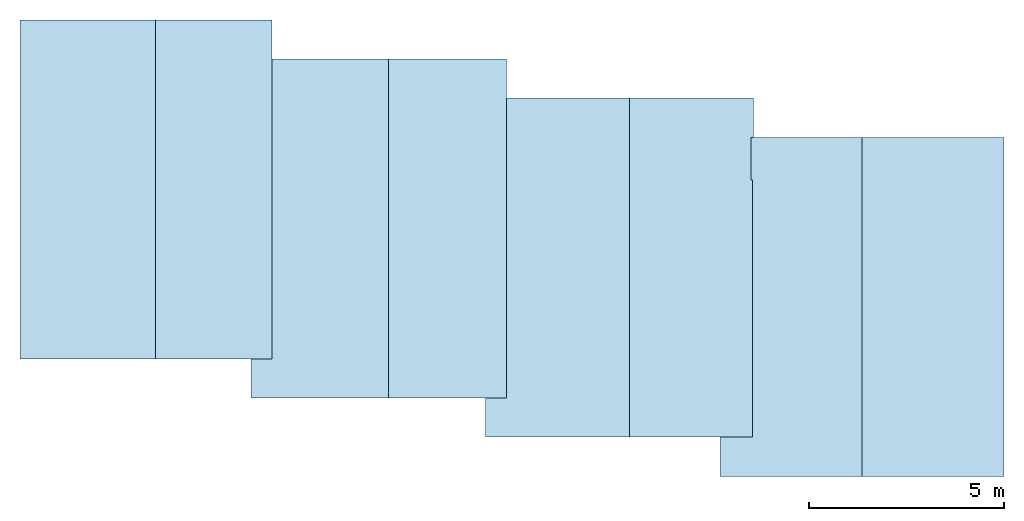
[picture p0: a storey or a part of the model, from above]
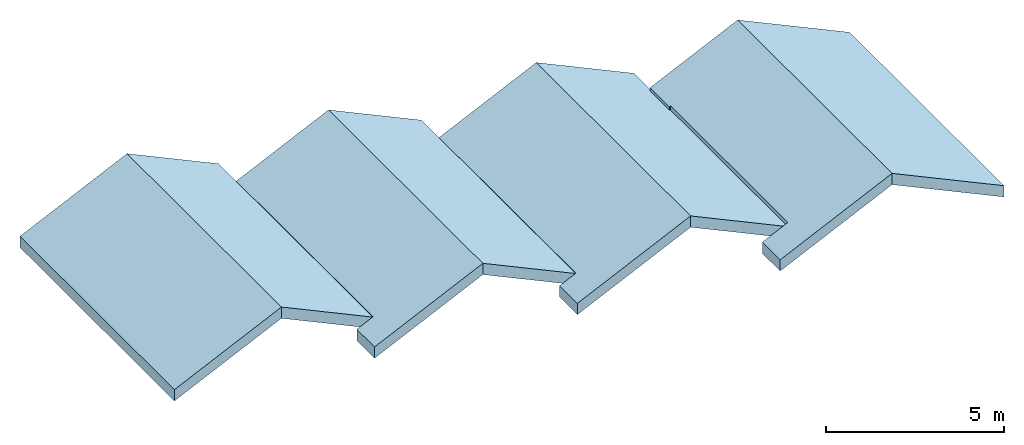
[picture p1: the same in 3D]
Properties of the parts of a building model (IFC2X3)

# File
Description: ViewDefinition [CoordinationView_V2.0], RevitIdentifiers [ContentGUID: f3c95b2a-3cce-4d3e-a499-3f45440ba017, VersionGUID: e7a1cec6-75d4-45cd-a237-02611641ebe7, NumberOfSaves: 51], CoordinateReference [CoordinateBase: Shared Coordinates]
File name: Skogtun nytt bygg.ifc
Time: 2026-06-24T11:29:21+01:00
Written by: ODA SDAI 25.12
Made in: Autodesk - Revit 26.3.0.37 (ENU) - 26.3.0.37

# IfcProject, 2009
LongName: Skogtun nye boliger; Phase: Prosjektstatus

# IfcSite, Default
RefLatitude: 59, 55, 1, 432800; RefLongitude: 10, 43, 39, 810104; RefElevation: 0 mm

# IfcBuilding
Pset_BuildingCommon - NumberOfStoreys: 4

# IfcBuildingStorey (4)
Pset_AirSideSystemInformation - sets with these values: 2
Name | LongName = Name | Elevation (mm)
Et. 1 | Et. 1 | 0
Et. 2 | Et. 2 | 2681
Gesims | Gesims | 5081
Møne | Møne | 6650

# IfcSpace: Area 1:1055046, 1
In: Et. 1
LongName: Area; InteriorOrExteriorSpace: INTERNAL; Group: Gross Building
Pset_AirSideSystemInformation - Name: Area; sets with these values: 2
Pset_SpaceCommon - Reference: Area 1

# IfcSpace: Bad 203:1075184, 203
In: Et. 2
LongName: Bad; InteriorOrExteriorSpace: INTERNAL
Pset_AirSideSystemInformation - Name: Bad; sets with these values: 2
Pset_SpaceCommon - Reference: Bad 203

# IfcSpace: Bad 207:1079033, 207
In: Et. 2
LongName: Bad; InteriorOrExteriorSpace: INTERNAL
Pset_AirSideSystemInformation - Name: Bad; sets with these values: 2
Pset_SpaceCommon - Reference: Bad 207

# IfcSpace: Bad 211:1079045, 211
In: Et. 2
LongName: Bad; InteriorOrExteriorSpace: INTERNAL
Pset_AirSideSystemInformation - Name: Bad; sets with these values: 2
Pset_SpaceCommon - Reference: Bad 211

# IfcSpace: Bad 215:1079057, 215
In: Et. 2
LongName: Bad; InteriorOrExteriorSpace: INTERNAL
Pset_AirSideSystemInformation - Name: Bad; sets with these values: 2
Pset_SpaceCommon - Reference: Bad 215

# IfcSpace: Bod 104:1043827, 104
In: Et. 1
LongName: Bod; InteriorOrExteriorSpace: INTERNAL
Pset_AirSideSystemInformation - Name: Bod; sets with these values: 2
Pset_SpaceCommon - Reference: Bod 104

# IfcSpace: Bod 108:1043835, 108
In: Et. 1
LongName: Bod; InteriorOrExteriorSpace: INTERNAL
Pset_AirSideSystemInformation - Name: Bod; sets with these values: 2
Pset_SpaceCommon - Reference: Bod 108

# IfcSpace: Bod 112:1043838, 112
In: Et. 1
LongName: Bod; InteriorOrExteriorSpace: INTERNAL
Pset_AirSideSystemInformation - Name: Bod; sets with these values: 2
Pset_SpaceCommon - Reference: Bod 112

# IfcSpace: Bod 116:1043841, 116
In: Et. 1
LongName: Bod; InteriorOrExteriorSpace: INTERNAL
Pset_AirSideSystemInformation - Name: Bod; sets with these values: 2
Pset_SpaceCommon - Reference: Bod 116

# IfcSpace: Gang 103:1063782, 103
In: Et. 1
LongName: Gang; InteriorOrExteriorSpace: INTERNAL
Pset_AirSideSystemInformation - Name: Gang; sets with these values: 2
Pset_SpaceCommon - Reference: Gang 103

# IfcSpace: Gang 107:1080082, 107
In: Et. 1
LongName: Gang; InteriorOrExteriorSpace: INTERNAL
Pset_AirSideSystemInformation - Name: Gang; sets with these values: 2
Pset_SpaceCommon - Reference: Gang 107

# IfcSpace: Gang 111:1080092, 111
In: Et. 1
LongName: Gang; InteriorOrExteriorSpace: INTERNAL
Pset_AirSideSystemInformation - Name: Gang; sets with these values: 2
Pset_SpaceCommon - Reference: Gang 111

# IfcSpace: Gang 115:1080101, 115
In: Et. 1
LongName: Gang; InteriorOrExteriorSpace: INTERNAL
Pset_AirSideSystemInformation - Name: Gang; sets with these values: 2
Pset_SpaceCommon - Reference: Gang 115

# IfcSpace: Gang 204:1075187, 204
In: Et. 2
LongName: Gang; InteriorOrExteriorSpace: INTERNAL
Pset_AirSideSystemInformation - Name: Gang; sets with these values: 2
Pset_SpaceCommon - Reference: Gang 204

# IfcSpace: Gang 208:1079036, 208
In: Et. 2
LongName: Gang; InteriorOrExteriorSpace: INTERNAL
Pset_AirSideSystemInformation - Name: Gang; sets with these values: 2
Pset_SpaceCommon - Reference: Gang 208

# IfcSpace: Gang 212:1079048, 212
In: Et. 2
LongName: Gang; InteriorOrExteriorSpace: INTERNAL
Pset_AirSideSystemInformation - Name: Gang; sets with these values: 2
Pset_SpaceCommon - Reference: Gang 212

# IfcSpace: Gang 216:1079060, 216
In: Et. 2
LongName: Gang; InteriorOrExteriorSpace: INTERNAL
Pset_AirSideSystemInformation - Name: Gang; sets with these values: 2
Pset_SpaceCommon - Reference: Gang 216

# IfcSpace: Soverom 201:1075173, 201
In: Et. 2
LongName: Soverom; InteriorOrExteriorSpace: INTERNAL
Pset_AirSideSystemInformation - Name: Soverom; sets with these values: 2
Pset_SpaceCommon - Reference: Soverom 201

# IfcSpace: Soverom 202:1075181, 202
In: Et. 2
LongName: Soverom; InteriorOrExteriorSpace: INTERNAL
Pset_AirSideSystemInformation - Name: Soverom; sets with these values: 2
Pset_SpaceCommon - Reference: Soverom 202

# IfcSpace: Soverom 205:1079027, 205
In: Et. 2
LongName: Soverom; InteriorOrExteriorSpace: INTERNAL
Pset_AirSideSystemInformation - Name: Soverom; sets with these values: 2
Pset_SpaceCommon - Reference: Soverom 205

# IfcSpace: Soverom 206:1079030, 206
In: Et. 2
LongName: Soverom; InteriorOrExteriorSpace: INTERNAL
Pset_AirSideSystemInformation - Name: Soverom; sets with these values: 2
Pset_SpaceCommon - Reference: Soverom 206

# IfcSpace: Soverom 209:1079039, 209
In: Et. 2
LongName: Soverom; InteriorOrExteriorSpace: INTERNAL
Pset_AirSideSystemInformation - Name: Soverom; sets with these values: 2
Pset_SpaceCommon - Reference: Soverom 209

# IfcSpace: Soverom 210:1079042, 210
In: Et. 2
LongName: Soverom; InteriorOrExteriorSpace: INTERNAL
Pset_AirSideSystemInformation - Name: Soverom; sets with these values: 2
Pset_SpaceCommon - Reference: Soverom 210

# IfcSpace: Soverom 213:1079051, 213
In: Et. 2
LongName: Soverom; InteriorOrExteriorSpace: INTERNAL
Pset_AirSideSystemInformation - Name: Soverom; sets with these values: 2
Pset_SpaceCommon - Reference: Soverom 213

# IfcSpace: Soverom 214:1079054, 214
In: Et. 2
LongName: Soverom; InteriorOrExteriorSpace: INTERNAL
Pset_AirSideSystemInformation - Name: Soverom; sets with these values: 2
Pset_SpaceCommon - Reference: Soverom 214

# IfcSpace: Stue/Kjøkken 101:1063785, 101
In: Et. 1
LongName: Stue/Kjøkken; InteriorOrExteriorSpace: INTERNAL
Pset_AirSideSystemInformation - Name: Stue/Kjøkken; sets with these values: 2
Pset_SpaceCommon - Reference: Stue/Kjøkken 101

# IfcSpace: Stue/Kjøkken 105:1080072, 105
In: Et. 1
LongName: Stue/Kjøkken; InteriorOrExteriorSpace: INTERNAL
Pset_AirSideSystemInformation - Name: Stue/Kjøkken; sets with these values: 2
Pset_SpaceCommon - Reference: Stue/Kjøkken 105

# IfcSpace: Stue/Kjøkken 109:1080085, 109
In: Et. 1
LongName: Stue/Kjøkken; InteriorOrExteriorSpace: INTERNAL
Pset_AirSideSystemInformation - Name: Stue/Kjøkken; sets with these values: 2
Pset_SpaceCommon - Reference: Stue/Kjøkken 109

# IfcSpace: Stue/Kjøkken 113:1080095, 113
In: Et. 1
LongName: Stue/Kjøkken; InteriorOrExteriorSpace: INTERNAL
Pset_AirSideSystemInformation - Name: Stue/Kjøkken; sets with these values: 2
Pset_SpaceCommon - Reference: Stue/Kjøkken 113

# IfcSpace: WC 102:1063779, 102
In: Et. 1
LongName: WC; InteriorOrExteriorSpace: INTERNAL
Pset_AirSideSystemInformation - Name: WC; sets with these values: 2
Pset_SpaceCommon - Reference: WC 102

# IfcSpace: WC 106:1080079, 106
In: Et. 1
LongName: WC; InteriorOrExteriorSpace: INTERNAL
Pset_AirSideSystemInformation - Name: WC; sets with these values: 2
Pset_SpaceCommon - Reference: WC 106

# IfcSpace: WC 110:1080089, 110
In: Et. 1
LongName: WC; InteriorOrExteriorSpace: INTERNAL
Pset_AirSideSystemInformation - Name: WC; sets with these values: 2
Pset_SpaceCommon - Reference: WC 110

# IfcSpace: WC 114:1080098, 114
In: Et. 1
LongName: WC; InteriorOrExteriorSpace: INTERNAL
Pset_AirSideSystemInformation - Name: WC; sets with these values: 2
Pset_SpaceCommon - Reference: WC 114

# IfcBuildingElementProxy: HC-Sirkel:HC-Sirkel 1500 (4)
Type - Material: <Unnamed>
Pset_BuildingElementProxyCommon - Reference: HC-Sirkel 1500; sets with these values: 2
Name (HC-Sirkel:HC-Sirkel 1500:...) | In
1074592 | 203
1075893 | 207
1076030 | 211
1076237 | 215

# IfcBuildingElementProxy: Kombiskap:Kombiskap (4)
Type - Material: Kjøkken - Hvitevarer
Pset_BuildingElementProxyCommon - Reference: Kombiskap; sets with these values: 2
Name (Kombiskap:Kombiskap:...) | In
1079378 | 113
1089154 | 109
1089204 | 105
1089252 | 101

# IfcBuildingElementProxy: Komfyr:Komfyr (4)
Type - Material: <Unnamed>, Focus - Material - Platetopp, Kjøkken - Hvitevarer, Kjøkken - Hvitevarer Glass, Material Stekeovn
Pset_BuildingElementProxyCommon - Reference: Komfyr; sets with these values: 2
Name (Komfyr:Komfyr:...) | In
1079377 | 113
1089153 | 109
1089203 | 105
1089251 | 101

# IfcBuildingElementProxy: Vaskesøyle:Vaskesøyle (4)
Type - Material: Bad-Vask-Maskin-Hvit, Stål-Børstet, Plastikk - Sort, Bad-Vask-Maskin-Glass
Pset_BuildingElementProxyCommon - Reference: Vaskesøyle; sets with these values: 2
Name (Vaskesøyle:Vaskesøyle:...) | In
1072654 | 203
1075889 | 207
1076026 | 211
1076233 | 215

# IfcColumn: Limtre-søyle:Limtre 90x90 (2)
Type - PredefinedType: COLUMN; Material: Limtre - GL30c
Type - Pset_ColumnCommon - LoadBearing: yes
Pset_ColumnCommon - IsExternal: no; Reference: Limtre 90x90
Pset_QuantityTakeOff - Reference: Limtre 90x90; sets with these values: 2
Name (Limtre-søyle:Limtre 90x90:...) | In
896741 | Et. 1 | Pset_ColumnCommon - Slope: 0 deg
1055478 | Et. 2

# IfcCovering: Fascia:Vindski, Fascia:Vindski:1044949
In: Et. 1
Type - Pset_CoveringCommon - Material: Maling - Hvit
Material: Maling - Hvit
Pset_CoveringCommon - Reference: Vindski; sets with these values: 2

# IfcDoor: ID Hel:9x21M (8)
Type - OperationType: SINGLE_SWING_LEFT; ParameterTakesPrecedence: no; Sizeable: no; Material: Dør - Håndtak, Karm, Dør - Dørblad
Type - ID Hel:9x21M:1059161:1 - PanelOperation: SWINGING
OverallHeight: 2100 mm; OverallWidth: 910 mm
Pset_DoorCommon - IsExternal: no; Reference: 9x21M
Pset_QuantityTakeOff - Reference: 9x21M
Name (ID Hel:9x21M:...) | In
1059161 | Et. 1
1073074 | Et. 2
1075891 | Et. 2
1076028 | Et. 2
1076235 | Et. 2
1079270 | Et. 1
1079330 | Et. 1
1079388 | Et. 1

# IfcDoor: ID Hel:9x21M (8)
In: Et. 2
Type - OperationType: SINGLE_SWING_RIGHT; ParameterTakesPrecedence: no; Sizeable: no; Material: Dør - Håndtak, Karm, Dør - Dørblad
Type - ID Hel:9x21M:1073016:1 - PanelOperation: SWINGING
OverallHeight: 2100 mm; OverallWidth: 910 mm
Pset_DoorCommon - IsExternal: no; Reference: 9x21M
Pset_QuantityTakeOff - Reference: 9x21M
Name (ID Hel:9x21M:...)
1073016
1073219
1075890
1075892
1076027
1076029
1076234
1076236

# IfcDoor: YD 1 Glassfelt omramming:10x21M (4)
In: Et. 1
Type - OperationType: SINGLE_SWING_RIGHT; ParameterTakesPrecedence: no; Sizeable: no; Material: Karm, Dør - Håndtak, Glass - Klart, Dør - Dørblad, Dør - Terskel - Eik
Type - YD 1 Glassfelt omramming:10x21M:887120:1 - PanelOperation: SWINGING
OverallHeight: 2100 mm; OverallWidth: 1010 mm
Pset_DoorCommon - IsExternal: yes; Reference: 10x21M
Pset_QuantityTakeOff - Reference: 10x21M
Name (YD 1 Glassfelt omramming:10x21M:...)
887120
887285
887393
887469

# IfcDoor: YD Dynamiske sprosser omramming:9x21M (4)
In: Et. 2
Type - ParameterTakesPrecedence: no; Sizeable: no; Material: Dør - Dørblad, Karm, Dør - Håndtak, Glass - Klart, Dør - Terskel - Eik
OverallHeight: 2100 mm; OverallWidth: 910 mm
Pset_DoorCommon - IsExternal: yes; Reference: 9x21M
Pset_QuantityTakeOff - Reference: 9x21M
Name (YD Dynamiske sprosser omramming:9x21M:...)
918485
918542
1065238
1078465

# IfcDoor: YD Hel omramming:10x21M (4)
In: Et. 1
Type - OperationType: SINGLE_SWING_LEFT; ParameterTakesPrecedence: no; Sizeable: no; Material: Karm, Dør - Håndtak, Dør - Dørblad, Dør - Terskel - Eik
Type - YD Hel omramming:10x21M:893311:1 - PanelOperation: SWINGING
OverallHeight: 2100 mm; OverallWidth: 1010 mm
Pset_DoorCommon - IsExternal: yes; Reference: 10x21M
Pset_QuantityTakeOff - Reference: 10x21M
Name (YD Hel omramming:10x21M:...)
893311
893358
893382
893453

# IfcFlowTerminal: Dusjkabinett:315_Dusjkabinett_900x900mm (4)
Type - Material: Bad-Innredning-Krom, Bad-Innredning-Glass-Klar, Bad-Innredning-Porselen, Bad-Innredning-dusjkabinett-Hvit
Pset_DistributionFlowElementCommon - Reference: 315_Dusjkabinett_900x900mm; sets with these values: 2
Name (Dusjkabinett:315_Dusjkabinett_900x900mm:...) | In
988469 | 203
1075785 | 207
1075992 | 211
1076199 | 215

# IfcFlowTerminal: Focus-Toalett gulv 1:Focus-Toalett gulv 1 (8)
Type - Material: Focus - VVS - Toalett, Focus - VVS - Toalett lokk, Focus - VVS - Krom
Pset_DistributionFlowElementCommon - Reference: Focus-Toalett gulv 1; sets with these values: 2
Name (Focus-Toalett gulv 1:Focus-Toalett gulv 1:...) | In
929392 | 102
989158 | 203
1075787 | 207
1075994 | 211
1076201 | 215
1079249 | 106
1079309 | 110
1079367 | 114

# IfcFlowTerminal: Klassisk - Kjøkkenvask 1,5 kum:600mm høyre (4)
Type - Material: Steel, Chrome Plated, Focus - Kjøkken - Kran, <Unnamed>, Focus - Kjøkken - Vask
Pset_DistributionFlowElementCommon - Reference: 600mm høyre; sets with these values: 2
Name (Klassisk - Kjøkkenvask 1,5 kum:600mm høyre:...) | In
1079379 | 113
1089155 | 109
1089205 | 105
1089253 | 101

# IfcFurnishingElement: Bad_Innredning_Indigo_600:274-IK-Vågen-600 (8)
Type - Material: Bad-Innredning-Krom, Bad-Innredning-Porselen, Bad-Innredning-Skrog, Bad-Innredning-Front-Hvit, Bad-Innredning-Speil, Bad-Innredning-Håndtak-Stål
Pset_QuantityTakeOff - Reference: 274-IK-Vågen-600
Name (Bad_Innredning_Indigo_600:274-IK-Vågen-600:...) | In
922596 | 102
989017 | 203
1075786 | 207
1075993 | 211
1076200 | 215
1079248 | 106
1079308 | 110
1079366 | 114

# IfcFurnishingElement: Focus - Håndtak Skap:Håndtak skap (28)
Type - Material: Focus - Kjøkken - Håndtak
Pset_QuantityTakeOff - Reference: Håndtak skap
Name (Focus - Håndtak Skap:Håndtak skap:...) | In
1079375 | 113
1079376 | 113
1086313 | 113
1088307 | 113
1088308 | 113
1089151 | 109
1089152 | 109
1089161 | 109
1089163 | 109
1089164 | 109
1089201 | 105
1089202 | 105
1089211 | 105
1089213 | 105
1089214 | 105
1089249 | 101
1089250 | 101
1089259 | 101
1089261 | 101
1089262 | 101
1096429 | 113
1096430 | 113
1096527 | 113
1096528 | 113
1097146 | 113
1097147 | 113
1097175 | 113
1097176 | 113

# IfcFurnishingElement: Focus - Håndtak Skuff:Håndtak skuff (24)
Type - Material: Focus - Kjøkken - Håndtak
Pset_QuantityTakeOff - Reference: Håndtak skuff
Name (Focus - Håndtak Skuff:Håndtak skuff:...) | In
1079371 | 113
1079372 | 113
1079373 | 113
1079391 | 113
1079392 | 113
1079393 | 113
1089147 | 109
1089148 | 109
1089149 | 109
1089157 | 109
1089158 | 109
1089159 | 109
1089197 | 105
1089198 | 105
1089199 | 105
1089207 | 105
1089208 | 105
1089209 | 105
1089245 | 101
1089246 | 101
1089247 | 101
1089255 | 101
1089256 | 101
1089257 | 101

# IfcFurnishingElement: Focus - Kjøkken - Benkeplate Hjørne:Focus - Kjøkken - Benkeplate Hjørne (4)
Type - Material: Focus - Material - Benkeplate
Pset_QuantityTakeOff - Reference: Focus - Kjøkken - Benkeplate Hjørne
Name (Focus - Kjøkken - Benkeplate Hjørne:Focus - Kjøkken - Benkeplate Hjørne:...) | In
1088530 | 113
1089165 | 109
1089215 | 105
1089263 | 101

# IfcFurnishingElement: Focus - Kjøkken - Benkeskap 2 dører:800 mm (4)
Type - Material: Focus - Kjøkken - Front, Focus - Kjøkken - Skapstamme
Pset_QuantityTakeOff - Reference: 800 mm
Name (Focus - Kjøkken - Benkeskap 2 dører:800 mm:...) | In
1079374 | 113
1089150 | 109
1089200 | 105
1089248 | 101

# IfcFurnishingElement: Focus - Kjøkken - Benkeskap 3 skuffer:600 mm (8)
Type - Material: Focus - Kjøkken - Front, Focus - Kjøkken - Skapstamme
Pset_QuantityTakeOff - Reference: 600 mm
Name (Focus - Kjøkken - Benkeskap 3 skuffer:600 mm:...) | In
1079370 | 113
1079390 | 113
1089146 | 109
1089156 | 109
1089196 | 105
1089206 | 105
1089244 | 101
1089254 | 101

# IfcFurnishingElement: Focus - Kjøkken - Benkeskap Hjørne:1000x650 mm (4)
Type - Material: Focus - Kjøkken - Front, Focus - Kjøkken - Skapstamme
Pset_QuantityTakeOff - Reference: 1000x650 mm
Name (Focus - Kjøkken - Benkeskap Hjørne:1000x650 mm:...) | In
1086312 | 113
1089160 | 109
1089210 | 105
1089258 | 101

# IfcFurnishingElement: Focus - Kjøkken - Høyskap 2 dører:600 mm (4)
Type - Material: Focus - Kjøkken - Front, Focus - Kjøkken - Skapstamme
Pset_QuantityTakeOff - Reference: 600 mm
Name (Focus - Kjøkken - Høyskap 2 dører:600 mm:...) | In
1088306 | 113
1089162 | 109
1089212 | 105
1089260 | 101

# IfcFurnishingElement: Focus - Kjøkken - Spiseplass:4 pers (4)
Type - Material: Focus - Møbler - Spisebord, Focus - Stolsete
Pset_QuantityTakeOff - Reference: 4 pers
Name (Focus - Kjøkken - Spiseplass:4 pers:...) | In
961817 | 101
1079251 | 105
1079311 | 109
1079369 | 113

# IfcFurnishingElement: Focus - Kjøkken - Veggskap 2 dør:600x370x400 (4)
In: 113
Type - Material: Focus - Kjøkken - Front, Focus - Kjøkken - Skapstamme
Pset_QuantityTakeOff - Reference: 600x370x400
Name (Focus - Kjøkken - Veggskap 2 dør:600x370x400:...)
1096428
1096526
1097145
1097174

# IfcFurnishingElement: Focus Garderobeskap - Skyvedører 2 slette:100x60x220 (8)
Type - Material: Møbler - Hvit
Pset_QuantityTakeOff - Reference: 100x60x220
Name (Focus Garderobeskap - Skyvedører 2 slette:100x60x220:...) | In
931345 | 103
985279 | 201
1075784 | 205
1075991 | 209
1076198 | 213
1079250 | 107
1079310 | 111
1079368 | 115

# IfcFurnishingElement: Focus Garderobeskap - Skyvedører 3 slette:150x60x220 (4)
Type - Material: Møbler - Hvit, Møbler - Grå mørk
Pset_QuantityTakeOff - Reference: 150x60x220
Name (Focus Garderobeskap - Skyvedører 3 slette:150x60x220:...) | In
996477 | 202
1075788 | 206
1075995 | 210
1076202 | 214

# IfcFurnishingElement: Focus Seng Dobbel-Kontinental:1500x2000 (4)
Type - Material: Focus-Møbler-Sengetøy-Grå, Focus-Møbler-Sengeteppe, Focus - Metall - Aluminium, Focus-Møbler-Sengetøy-Hvit, Focus-Møbler-Sengetøy-Grå mørk
Pset_QuantityTakeOff - Reference: 1500x2000
Name (Focus Seng Dobbel-Kontinental:1500x2000:...) | In
996842 | 202
1075789 | 206
1075996 | 210
1076203 | 214

# IfcFurnishingElement: Focus Seng Enkel-Kontinental:800x2000 (4)
Type - Material: Focus-Møbler-Sengetøy-Grå mørk, Focus - Metall - Aluminium, Focus-Møbler-Sengetøy-Hvit, Focus-Møbler-Sengeteppe
Pset_QuantityTakeOff - Reference: 800x2000
Name (Focus Seng Enkel-Kontinental:800x2000:...) | In
985016 | 201
1075783 | 205
1075990 | 209
1076197 | 213

# IfcFurnishingElement: Sofa Corbu:Sofa 2 seter (8)
Type - Material: Møbler - Lær - Sort, Metal - Chrome
Type - Pset_FurnitureTypeChair - SeatingHeight: 365 mm
Pset_QuantityTakeOff - Reference: Sofa 2 seter
Name (Sofa Corbu:Sofa 2 seter:...) | In
969405 | 101
974265 | 101
1079262 | 105
1079265 | 105
1079322 | 109
1079325 | 109
1079380 | 113
1079383 | 113

# IfcFurnishingElement: Stuebord (1):1200x600x450 (4)
Type - Material: Focus - Møbler - Kaffebord - Ramme, Focus - Møbler - Kaffebord - Glass
Pset_QuantityTakeOff - Reference: 1200x600x450
Name (Stuebord (1):1200x600x450:...) | In
974152 | 101
1079264 | 105
1079324 | 109
1079382 | 113

# IfcFurnishingElement: TV bord (1):TV bord 1800x400x300 (4)
Type - Material: Focus - TV - Sort, Focus - Metall - Krom, Focus - Møbler - Hvit
Pset_QuantityTakeOff - Reference: TV bord 1800x400x300
Name (TV bord (1):TV bord 1800x400x300:...) | In
973301 | 101
1079263 | 105
1079323 | 109
1079381 | 113

# IfcMember: Stringer:Vange - Tre 50mm bredde (32)
In: Et. 1
Type - PredefinedType: STRINGER
Material: Focus - Tre
Pset_MemberCommon - IsExternal: no; Reference: Vange - Tre 50mm bredde
Pset_QuantityTakeOff - Reference: Vange - Tre 50mm bredde
Name (Assembled Stair:Stair:...) | Slope (deg)
1057884 Stringer 1 | 28.1509
1057884 Stringer 2 | 0
1057884 Stringer 3 | 20.5637
1057884 Stringer 4 | 0
1057884 Stringer 5 | 28.1509
1057884 Stringer 6 | 52.2659
1057884 Stringer 7 | 68.0587
1057884 Stringer 8 | 52.2659
1075790 Stringer 1 | 28.1509
1075790 Stringer 2 | 0
1075790 Stringer 3 | 20.5637
1075790 Stringer 4 | 0
1075790 Stringer 5 | 28.1509
1075790 Stringer 6 | 52.2659
1075790 Stringer 7 | 68.0587
1075790 Stringer 8 | 52.2659
1075997 Stringer 1 | 28.1509
1075997 Stringer 2 | 0
1075997 Stringer 3 | 20.5637
1075997 Stringer 4 | 0
1075997 Stringer 5 | 28.1509
1075997 Stringer 6 | 52.2659
1075997 Stringer 7 | 68.0587
1075997 Stringer 8 | 52.2659
1076204 Stringer 1 | 28.1509
1076204 Stringer 2 | 0
1076204 Stringer 3 | 20.5637
1076204 Stringer 4 | 0
1076204 Stringer 5 | 28.1509
1076204 Stringer 6 | 52.2659
1076204 Stringer 7 | 68.0587
1076204 Stringer 8 | 52.2659

# IfcRailing: Railing:900mm (12)
Material: Metall - Malt - MØRK GRÅ MATT
Pset_QuantityTakeOff - Reference: 900mm
Pset_RailingCommon - IsExternal: no; Reference: 900mm; Height: 1219.2 mm
Name (Railing:900mm:...) | In
1025440 | Et. 2
1043479 | Et. 2
1058081 | Et. 1
1058085 | Et. 1
1072747 | Et. 2
1075801 | Et. 1
1075805 | Et. 1
1076008 | Et. 1
1076012 | Et. 1
1076215 | Et. 1
1076219 | Et. 1
1077657 | Et. 2

# IfcRailing: Railing:Balkong - Spiler Stående 900mm (4)
In: Et. 2
Material: Rekkverk - Tre
Pset_QuantityTakeOff - Reference: Balkong - Spiler Stående 900mm
Pset_RailingCommon - IsExternal: no; Reference: Balkong - Spiler Stående 900mm; Height: 900 mm
Name (Railing:Balkong - Spiler Stående 900mm:...)
898557
902497
905455
905766

# IfcRoof (8)
Material: Tak - Takstein - Sort 30 mm, Default Roof 21 mm, Default Roof 36 mm, Tak - Tre - Sperre - Isolert 250 mm, Tak - Gips - Hvit 13 mm
Pset_QuantityTakeOff - Reference: Taksperre, Steintekking Sort
Pset_RoofCommon - IsExternal: yes; Reference: Taksperre, Steintekking Sort
Name (Basic Roof:Taksperre, Steintekking Sort:...) | In | ProjectedArea (m2) | TotalArea (m2)
876887 | Gesims | 55.8692 | 61.6449
877015 | Gesims | 52.631 | 58.0719
877129 | Gesims | 55.3761 | 61.1007
877273 | Gesims | 56.6703 | 62.5288
894122 | Et. 2 | 14.9471 | 15.0042
894512 | Et. 2 | 15.1102 | 15.1679
894530 | Et. 2 | 15.114 | 15.1717
894550 | Et. 2 | 15.7689 | 15.8292

# IfcSlab: Basic Roof:Taksperre, Steintekking Sort (12)
Type - PredefinedType: ROOF
Type - Pset_ReinforcementBarPitchOfSlab - Description: Tak - Takstein - Sort (30mm) (21mm) (36mm) Tak - Membran (0mm) Tak - Tre - Sperre - Isolert (250mm) Tak - Gips - Hvit (13mm)
Material: Tak - Takstein - Sort 30 mm, Default Roof 21 mm, Default Roof 36 mm, Tak - Tre - Sperre - Isolert 250 mm, Tak - Gips - Hvit 13 mm
Pset_QuantityTakeOff - Reference: Taksperre, Steintekking Sort; sets with these values: 2
Pset_SlabCommon - IsExternal: yes; Reference: Taksperre, Steintekking Sort
Name (Basic Roof:Taksperre, Steintekking Sort:...) | In | PitchAngle (deg)
2 x 876887 | Gesims | 25
2 x 877015 | Gesims | 25
2 x 877129 | Gesims | 25
2 x 877273 | Gesims | 25
894122 | Et. 2 | 5
894512 | Et. 2 | 5
894530 | Et. 2 | 5
894550 | Et. 2 | 5

# IfcSlab: Floor:25-B-250 (4)
In: Et. 1
Type - PredefinedType: FLOOR; Material: Dekke - Betong - Plasstøpt - Ubehandlet 250 mm
Type - Pset_ReinforcementBarPitchOfSlab - Description: Dekke - Betong - Plasstøpt - Ubehandlet (250mm)
Pset_QuantityTakeOff - Reference: 25-B-250; sets with these values: 2
Pset_SlabCommon - LoadBearing: no; IsExternal: no; PitchAngle: 0 deg; Reference: 25-B-250
Name (Floor:25-B-250:...)
880311
880431
880586
880683

# IfcSlab: Floor:25-Etasjeskille SpTISp-22_223_23_13 (4)
In: Et. 2
Type - PredefinedType: FLOOR; Material: Dekke - Spon 22 mm, Dekke - Bjelke tre - Isolert 223 mm, Dekke - Luftskikt 23 mm, Dekke - Gips 13 mm
Type - Pset_ReinforcementBarPitchOfSlab - Description: Dekke - Spon (22mm) Dekke - Bjelke tre - Isolert (223mm) Dekke - Luftskikt (23mm) Dekke - Gips (13mm)
Pset_QuantityTakeOff - Reference: 25-Etasjeskille SpTISp-22_223_23_13; sets with these values: 2
Pset_SlabCommon - LoadBearing: no; IsExternal: no; PitchAngle: 0 deg; Reference: 25-Etasjeskille SpTISp-22_223_23_13
Name (Floor:25-Etasjeskille SpTISp-22_223_23_13:...)
876533
876575
876689
876779

# IfcSlab: Floor:25-Gulv på grunn SpBIhGr-22_50_200_100, Floor:25-Gulv på grunn SpBIhGr-22_50_200_100:873167
In: Et. 1
Type - PredefinedType: FLOOR; Material: Dekke - Spon 22 mm, Dekke - Betong - Plasstøpt - Ubehandlet 50 mm, Dekke - Hard - Isolasjon 200 mm, Utendørs - Grus 100 mm
Type - Pset_ReinforcementBarPitchOfSlab - Description: Dekke - Spon (22mm) Dekke - Betong - Plasstøpt - Ubehandlet (50mm) Dekke - Hard - Isolasjon (200mm) Utendørs - Grus (100mm)
Pset_QuantityTakeOff - Reference: 25-Gulv på grunn SpBIhGr-22_50_200_100; sets with these values: 2
Pset_SlabCommon - LoadBearing: no; IsExternal: no; Reference: 25-Gulv på grunn SpBIhGr-22_50_200_100; PitchAngle: 0 deg

# IfcSlab: Floor:25-TbTU-22_148 (4)
In: Et. 1
Type - PredefinedType: FLOOR; Material: Dekke - Terrassebord 28 mm, Dekke - Bjelke tre - Impregnert 148 mm
Type - Pset_ReinforcementBarPitchOfSlab - Description: Dekke - Terrassebord (28mm) Dekke - Bjelke tre - Impregnert (148mm)
Pset_QuantityTakeOff - Reference: 25-TbTU-22_148; sets with these values: 2
Pset_SlabCommon - IsExternal: yes; LoadBearing: no; PitchAngle: 0 deg; Reference: 25-TbTU-22_148
Name (Floor:25-TbTU-22_148:...)
880847
880917
880945
881042

# IfcSlab: Floor:25-TbTU-22_balkong (4)
In: Et. 2
Type - PredefinedType: FLOOR; Material: Dekke - Terrassebord 28 mm, Dekke - Spon 10 mm
Type - Pset_ReinforcementBarPitchOfSlab - Description: Dekke - Terrassebord (28mm) Dekke - Bjelke tre - Impregnert (148mm)
Pset_QuantityTakeOff - Reference: 25-TbTU-22_balkong; sets with these values: 2
Pset_SlabCommon - IsExternal: yes; LoadBearing: no; PitchAngle: 0 deg; Reference: 25-TbTU-22_balkong
Name (Floor:25-TbTU-22_balkong:...)
898030
901805
904741
905741

# IfcStair: Assembled Stair:Tretrapp - Åpne trinn m/ vanger (4)
In: Et. 1
Pset_QuantityTakeOff - Reference: Tretrapp - Åpne trinn m/ vanger
Pset_StairCommon - IsExternal: no; Reference: Tretrapp - Åpne trinn m/ vanger; NumberOfRiser: 15; NumberOfTreads: 14; RiserHeight: 178.733 mm; TreadLength: 240 mm
Name (Assembled Stair:Stair:...)
1057884
1075790
1075997
1076204

# IfcStairFlight: Non-Monolithic Run:Tretrinn - 20mm Trinnese (4)
In: Et. 1
Type - PredefinedType: WINDER
Type - Pset_StairFlightCommon - NosingLength: 20 mm
NumberOfRiser: 15; NumberOfTreads: 14; RiserHeight: 0.586395 mm; TreadLength: 0.787402 mm; Material: Focus - Tre
Pset_QuantityTakeOff - Reference: Tretrinn - 20mm Trinnese
Pset_StairFlightCommon - Reference: Tretrinn - 20mm Trinnese; NumberOfRiser: 15; NumberOfTreads: 14; RiserHeight: 178.733 mm; TreadLength: 240 mm; WalkingLineOffset: 1.47638 mm; TreadLengthAtOffset: 240 mm; TreadLengthAtInnerSide: 240 mm
Name (Assembled Stair:Stair:...)
1057884 Run 1
1075790 Run 1
1075997 Run 1
1076204 Run 1

# IfcWallStandardCase: Basic Wall:23-Kv(sm)TIG-19_36_23_9_198_48_13 (40)
Type - PredefinedType: STANDARD; Material: Vegg - Stående Kledning_smal - HVIT 19 mm, Vegg - Utlekting 36 mm, Vegg - Utlekting 23 mm, Vegg - Gips - GU 9 mm, Vegg - Stender - Isolert 198 mm, Vegg - Påforing - Isolert 48 mm, Vegg - Gips - Hvit 13 mm
Type - Pset_ReinforcementBarPitchOfWall - Description: Vegg - Stående Kledning_smal - HVIT (19mm) Vegg - Utlekting (36mm) Vegg - Utlekting (23mm) Vegg - Gips - GU (9mm) Vegg - Stender - Isolert (198mm) Vegg - Påforing - Isolert (48mm) Vegg - Gips - Hvit (13mm)
Pset_QuantityTakeOff - Reference: 23-Kv(sm)TIG-19_36_23_9_198_48_13; sets with these values: 2
Pset_WallCommon - Reference: 23-Kv(sm)TIG-19_36_23_9_198_48_13; IsExternal: yes; LoadBearing: no
Name (Basic Wall:23-Kv(sm)TIG-19_36_23_9_198_48_13:...) | In | ExtendToStructure
871850 | Et. 1 | no
871905 | Et. 1 | no
871940 | Et. 1 | no
872010 | Et. 1 | no
872042 | Et. 1 | no
872105 | Et. 1 | no
872137 | Et. 1 | no
872185 | Et. 1 | no
872252 | Et. 1 | no
872298 | Et. 1 | no
872337 | Et. 1 | no
872382 | Et. 1 | no
872417 | Et. 1 | no
872461 | Et. 1 | no
872492 | Et. 1 | no
872539 | Et. 1 | no
873641 | Et. 2 | yes
873708 | Et. 2 | yes
873758 | Et. 2 | no
873927 | Et. 2 | yes
874070 | Et. 2 | no
874218 | Et. 2 | yes
874436 | Et. 2 | no
874587 | Et. 2 | yes
874722 | Et. 2 | yes
874814 | Et. 2 | yes
875035 | Et. 2 | no
875213 | Et. 2 | yes
875316 | Et. 2 | no
875446 | Et. 2 | yes
875587 | Et. 2 | no
875705 | Et. 2 | yes
897262 | Et. 2 | yes
897312 | Et. 2 | yes
901629 | Et. 2 | yes
901699 | Et. 2 | yes
903989 | Et. 2 | yes
904089 | Et. 2 | yes
904493 | Et. 2 | yes
904547 | Et. 2 | yes

# IfcWallStandardCase: Basic Wall:23-Kv(sm)TIG-19_Bod (12)
In: Et. 1
Type - PredefinedType: STANDARD; Material: Vegg - Stående Kledning_smal - HVIT 19 mm, Vegg - Stender - Isolert 198 mm
Type - Pset_ReinforcementBarPitchOfWall - Description: Vegg - Stående Kledning_smal - HVIT (19mm) Vegg - Utlekting (36mm) Vegg - Utlekting (23mm) Vegg - Gips - GU (9mm) Vegg - Stender - Isolert (198mm) Vegg - Påforing - Isolert (48mm) Vegg - Gips - Hvit (13mm)
Pset_QuantityTakeOff - Reference: 23-Kv(sm)TIG-19_Bod; sets with these values: 2
Pset_WallCommon - IsExternal: yes; LoadBearing: no; Reference: 23-Kv(sm)TIG-19_Bod
Name (Basic Wall:23-Kv(sm)TIG-19_Bod:...) | ExtendToStructure
879087 | yes
879145 | yes
879192 | yes
879270 | yes
879331 | yes
879389 | no
879496 | yes
879560 | yes
879609 | no
879694 | yes
879738 | yes
879797 | no

# IfcWallStandardCase: Basic Wall:24-GSIG-13_100_13 (37)
Type - PredefinedType: STANDARD; Material: Vegg - Gips - Innvendig - Hvit 13 mm, Vegg - Stender - Stål - Isolert 100 mm, Vegg - Gips - Innvendig - Hvit 13 mm
Type - Pset_ReinforcementBarPitchOfWall - Description: Vegg - Gips - Innvendig - Hvit (13mm) Vegg - Stender - Stål - Isolert (100mm) Vegg - Gips - Innvendig - Hvit (13mm)
Pset_QuantityTakeOff - Reference: 24-GSIG-13_100_13; sets with these values: 2
Pset_WallCommon - LoadBearing: no; IsExternal: no; Reference: 24-GSIG-13_100_13
Name (Basic Wall:24-GSIG-13_100_13:...) | In | ExtendToStructure
1058553 | Et. 1 | no
1058640 | Et. 1 | no
1058816 | Et. 1 | no
1059070 | Et. 1 | no
1064854 | Et. 2 | yes
1064889 | Et. 2 | no
1065020 | Et. 2 | yes
1065115 | Et. 2 | yes
1074917 | Et. 2 | yes
1075884 | Et. 2 | yes
1075885 | Et. 2 | yes
1075886 | Et. 2 | yes
1075887 | Et. 2 | yes
1075895 | Et. 2 | yes
1076022 | Et. 2 | yes
1076023 | Et. 2 | yes
1076024 | Et. 2 | yes
1076025 | Et. 2 | yes
1076031 | Et. 2 | yes
1076229 | Et. 2 | yes
1076230 | Et. 2 | yes
1076231 | Et. 2 | yes
1076232 | Et. 2 | yes
1076238 | Et. 2 | yes
1079266 | Et. 1 | no
1079267 | Et. 1 | no
1079268 | Et. 1 | no
1079269 | Et. 1 | no
1079326 | Et. 1 | no
1079327 | Et. 1 | no
1079328 | Et. 1 | no
1079329 | Et. 1 | no
1079384 | Et. 1 | no
1079385 | Et. 1 | no
1079386 | Et. 1 | no
1079387 | Et. 1 | no
1090577 | Et. 1 | no

# IfcWallStandardCase: Basic Wall:24-GSISIG-26_100_40_100_26 (6)
Type - PredefinedType: STANDARD; Material: Vegg - Gips - Innvendig - Hvit 13 mm, Vegg - Gips - Innvendig - Hvit 13 mm, Vegg - Stender - Isolert 100 mm, Vegg - Luftsjikt 40 mm, Vegg - Stender - Isolert 100 mm, Vegg - Gips - Innvendig - Hvit 13 mm, Vegg - Gips - Innvendig - Hvit 13 mm
Type - Pset_ReinforcementBarPitchOfWall - Description: Vegg - Gips - Innvendig - Hvit (13mm) Vegg - Gips - Innvendig - Hvit (13mm) Vegg - Stender - Isolert (100mm) Vegg - Luftsjikt (40mm) Vegg - Stender - Isolert (100mm) Vegg - Gips - Innvendig - Hvit (13mm) Vegg - Gips - Innvendig - Hvit (13mm)
Pset_QuantityTakeOff - Reference: 24-GSISIG-26_100_40_100_26; sets with these values: 2
Pset_WallCommon - LoadBearing: no; Reference: 24-GSISIG-26_100_40_100_26; IsExternal: no
Name (Basic Wall:24-GSISIG-26_100_40_100_26:...) | In | ExtendToStructure
872867 | Et. 1 | no
872970 | Et. 1 | no
873109 | Et. 1 | no
875810 | Et. 2 | yes
875936 | Et. 2 | yes
876059 | Et. 2 | yes

# IfcWindow: 2 ruter vert-post åpning-fast m omramming:14x11M (17)
Type - ParameterTakesPrecedence: no; Sizeable: no; Material: Omramming, Glass - Klart, Karm
OverallHeight: 1110 mm; OverallWidth: 1410 mm
Pset_QuantityTakeOff - Reference: 14x11M
Pset_WindowCommon - IsExternal: yes; Reference: 14x11M
Name (2 ruter vert-post åpning-fast m omramming:14x11M:...) | In
1034111 | Et. 1
1034225 | Et. 1
1034313 | Et. 1
1034393 | Et. 1
1034495 | Et. 1
1034571 | Et. 1
1034629 | Et. 1
1034707 | Et. 1
1034783 | Et. 1
1041806 | Et. 2
1041854 | Et. 2
1041902 | Et. 2
1041968 | Et. 2
1042062 | Et. 2
1042180 | Et. 2
1042238 | Et. 2
1065494 | Et. 2

# IfcWindow: Hel Rute Åpningsvindu m omramming:6x11M (4)
In: Et. 1
Type - ParameterTakesPrecedence: no; Sizeable: no; Material: Omramming, Karm, Glass - Klart
OverallHeight: 1110 mm; OverallWidth: 610 mm
Pset_QuantityTakeOff - Reference: 6x11M
Pset_WindowCommon - IsExternal: yes; Reference: 6x11M
Name (Hel Rute Åpningsvindu m omramming:6x11M:...)
1085054
1085134
1085178
1085236

# IfcWindow: Hel Rute Åpningsvindu m omramming:8x11M (4)
In: Et. 2
Type - ParameterTakesPrecedence: no; Sizeable: no; Material: Omramming, Karm, Glass - Klart
OverallHeight: 1110 mm; OverallWidth: 810 mm
Pset_QuantityTakeOff - Reference: 8x11M
Pset_WindowCommon - IsExternal: yes; Reference: 8x11M
Name (Hel Rute Åpningsvindu m omramming:8x11M:...)
1072321
1078687
1078755
1078825
